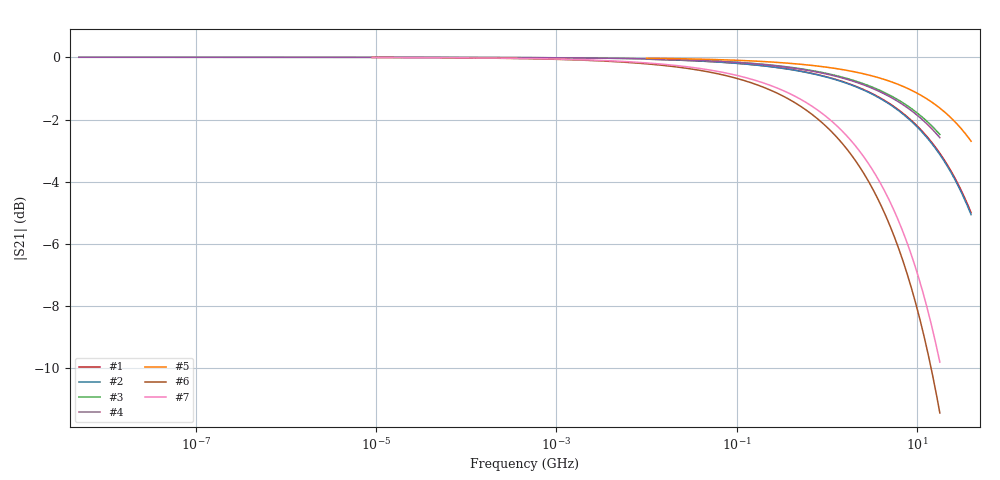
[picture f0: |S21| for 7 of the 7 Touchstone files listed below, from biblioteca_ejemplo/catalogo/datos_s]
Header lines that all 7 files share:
! CAL-ELEKTRA — DATOS SINTÉTICOS DE EJEMPLO: no son una medida real.
# HZ S RI R 50
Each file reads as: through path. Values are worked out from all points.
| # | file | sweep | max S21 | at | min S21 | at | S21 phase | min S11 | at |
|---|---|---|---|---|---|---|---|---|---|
| 1 | CAB-PT-292-01.s2p | 10 MHz to 40 GHz | -0.06 dB | 10 MHz | -5.0 dB | 40 GHz | 165 deg at 632.5 MHz | -30.7 dB | 88.21 MHz |
| 2 | CAB-PT-292-02.s2p | 10 MHz to 40 GHz | -0.06 dB | 10 MHz | -5.1 dB | 40 GHz | 165 deg at 632.5 MHz | -30.5 dB | 12.05 MHz |
| 3 | CAB-PT-N-01.s2p | 5 Hz to 18 GHz | 0.00 dB | 5 Hz | -2.5 dB | 18 GHz | -1 deg at 300 kHz | -32.9 dB | 853.2 kHz |
| 4 | CAB-PT-N-02.s2p | 5 Hz to 18 GHz | 0.00 dB | 5 Hz | -2.6 dB | 18 GHz | -1 deg at 300 kHz | -31.9 dB | 16.64 MHz |
| 5 | CAB-PT-NMD-01.s2p | 10 MHz to 40 GHz | -0.03 dB | 10 MHz | -2.7 dB | 40 GHz | 144 deg at 632.5 MHz | -28.7 dB | 32.61 MHz |
| 6 | PATH-RX-01.s2p | 9 kHz to 18 GHz | -0.01 dB | 9 kHz | -11.4 dB | 18 GHz | 84 deg at 12.73 MHz | -25.7 dB | 377.4 kHz |
| 7 | PATH-TX-01.s2p | 9 kHz to 18 GHz | -0.01 dB | 9 kHz | -9.8 dB | 18 GHz | 139 deg at 12.73 MHz | -26.9 dB | 4.287 MHz |
